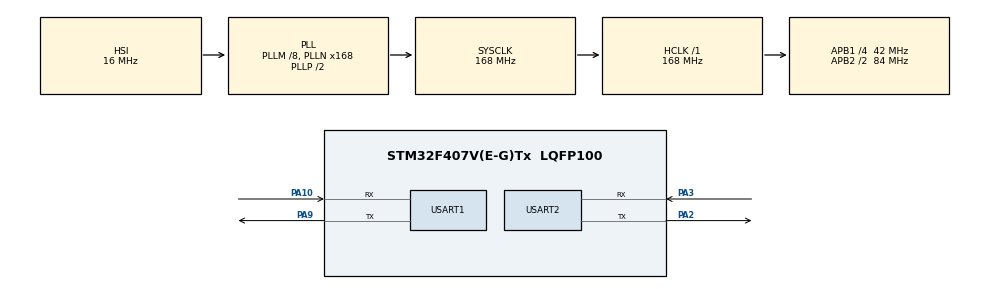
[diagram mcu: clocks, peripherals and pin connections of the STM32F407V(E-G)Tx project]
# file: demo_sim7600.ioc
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Mcu.Family=STM32F4
Mcu.Name=STM32F407V(E-G)Tx
Mcu.Package=LQFP100
NVIC.PriorityGroup=NVIC_PRIORITYGROUP_4
NVIC.USART1_IRQn=true\:0\:0\:false\:false\:true\:true\:true
NVIC.USART2_IRQn=true\:0\:0\:false\:false\:true\:true\:true
PA10.Mode=Asynchronous
PA10.Signal=USART1_RX
PA13.Mode=Serial_Wire
PA13.Signal=SYS_JTMS-SWDIO
PA14.Mode=Serial_Wire
PA14.Signal=SYS_JTCK-SWCLK
PA2.Mode=Asynchronous
PA2.Signal=USART2_TX
PA3.Mode=Asynchronous
PA3.Signal=USART2_RX
PA9.Mode=Asynchronous
PA9.Signal=USART1_TX
PH0-OSC_IN.Mode=HSE-External-Oscillator
PH0-OSC_IN.Signal=RCC_OSC_IN
PH1-OSC_OUT.Mode=HSE-External-Oscillator
PH1-OSC_OUT.Signal=RCC_OSC_OUT
ProjectManager.HeapSize=0x200
ProjectManager.StackSize=0x400
ProjectManager.TargetToolchain=STM32CubeIDE
RCC.48MHZClocksFreq_Value=84000000
RCC.AHBFreq_Value=168000000
RCC.APB1CLKDivider=RCC_HCLK_DIV4
RCC.APB1Freq_Value=42000000
RCC.APB1TimFreq_Value=84000000
RCC.APB2CLKDivider=RCC_HCLK_DIV2
RCC.APB2Freq_Value=84000000
RCC.APB2TimFreq_Value=168000000
RCC.CortexFreq_Value=168000000
RCC.HCLKFreq_Value=168000000
RCC.HSE_VALUE=25000000
RCC.HSI_VALUE=16000000
RCC.LSE_VALUE=32768
RCC.PLLM=8
RCC.PLLN=168
RCC.SYSCLKFreq_VALUE=168000000
RCC.SYSCLKSource=RCC_SYSCLKSOURCE_PLLCLK
RCC.VCOOutputFreq_Value=336000000
USART1.VirtualMode=VM_ASYNC
USART2.VirtualMode=VM_ASYNC
board=custom

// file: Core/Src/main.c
/* USER CODE BEGIN Header */
/**
  ******************************************************************************
  * @file           : main.c
  * @brief          : Main program body
  ******************************************************************************
  * @attention
  *
  * <h2><center>&copy; Copyright (c) 2021 STMicroelectronics.
  * All rights reserved.</center></h2>
  *
  * This software component is licensed by ST under BSD 3-Clause license,
  * the "License"; You may not use this file except in compliance with the
  * License. You may obtain a copy of the License at:
  *                        opensource.org/licenses/BSD-3-Clause
  *
  ******************************************************************************
  */
/* USER CODE END Header */
#include "main.h"
#include "sim7600.h"
#include "string.h"
#include "stdlib.h"

UART_HandleTypeDef huart1;
UART_HandleTypeDef huart2;

void SystemClock_Config(void);
static void MX_GPIO_Init(void);
static void MX_USART1_UART_Init(void);
static void MX_USART2_UART_Init(void);
/* USER CODE BEGIN PFP */
char payload[500];
/* USER CODE END PFP */

int main(void)
{

  /* MCU Configuration--------------------------------------------------------*/

  /* Reset of all peripherals, Initializes the Flash interface and the Systick. */
  HAL_Init();

  /* Configure the system clock */
  SystemClock_Config();

  /* Initialize all configured peripherals */
  MX_GPIO_Init();
  MX_USART1_UART_Init();
  MX_USART2_UART_Init();
  /* USER CODE BEGIN 2 */
  __HAL_UART_ENABLE_IT(&huart2, UART_IT_RXNE);
  INIT_SIM7600();
  SETUP_CONNECTION( "3.226.137.205","yktdxpqb","VKCG6yboYrYd",19613);
  /* USER CODE END 2 */
  /* Infinite loop */
  /* USER CODE BEGIN WHILE */
  while (1)
  {
	  PUBLISH_TELEMETRY("upstream/telemetry/608a78baaa969877dec4e6f4");
	  HAL_Delay(3000);
    /* USER CODE END WHILE */

  }
}

void SystemClock_Config(void)
{
  RCC_OscInitTypeDef RCC_OscInitStruct = {0};
  RCC_ClkInitTypeDef RCC_ClkInitStruct = {0};

  /** Configure the main internal regulator output voltage
  */
  __HAL_RCC_PWR_CLK_ENABLE();
  __HAL_PWR_VOLTAGESCALING_CONFIG(PWR_REGULATOR_VOLTAGE_SCALE1);
  /** Initializes the RCC Oscillators according to the specified parameters
  * in the RCC_OscInitTypeDef structure.
  */
  RCC_OscInitStruct.OscillatorType = RCC_OSCILLATORTYPE_HSI;
  RCC_OscInitStruct.HSIState = RCC_HSI_ON;
  RCC_OscInitStruct.HSICalibrationValue = RCC_HSICALIBRATION_DEFAULT;
  RCC_OscInitStruct.PLL.PLLState = RCC_PLL_ON;
  RCC_OscInitStruct.PLL.PLLSource = RCC_PLLSOURCE_HSI;
  RCC_OscInitStruct.PLL.PLLM = 8;
  RCC_OscInitStruct.PLL.PLLN = 168;
  RCC_OscInitStruct.PLL.PLLP = RCC_PLLP_DIV2;
  RCC_OscInitStruct.PLL.PLLQ = 4;
  if (HAL_RCC_OscConfig(&RCC_OscInitStruct) != HAL_OK)
  {
    Error_Handler();
  }
  /** Initializes the CPU, AHB and APB buses clocks
  */
  RCC_ClkInitStruct.ClockType = RCC_CLOCKTYPE_HCLK|RCC_CLOCKTYPE_SYSCLK
                              |RCC_CLOCKTYPE_PCLK1|RCC_CLOCKTYPE_PCLK2;
  RCC_ClkInitStruct.SYSCLKSource = RCC_SYSCLKSOURCE_PLLCLK;
  RCC_ClkInitStruct.AHBCLKDivider = RCC_SYSCLK_DIV1;
  RCC_ClkInitStruct.APB1CLKDivider = RCC_HCLK_DIV4;
  RCC_ClkInitStruct.APB2CLKDivider = RCC_HCLK_DIV2;

  if (HAL_RCC_ClockConfig(&RCC_ClkInitStruct, FLASH_LATENCY_5) != HAL_OK)
  {
    Error_Handler();
  }
}

static void MX_USART1_UART_Init(void)
{

  huart1.Instance = USART1;
  huart1.Init.BaudRate = 9600;
  huart1.Init.WordLength = UART_WORDLENGTH_8B;
  huart1.Init.StopBits = UART_STOPBITS_1;
  huart1.Init.Parity = UART_PARITY_NONE;
  huart1.Init.Mode = UART_MODE_TX_RX;
  huart1.Init.HwFlowCtl = UART_HWCONTROL_NONE;
  huart1.Init.OverSampling = UART_OVERSAMPLING_16;
  if (HAL_UART_Init(&huart1) != HAL_OK)
  {
    Error_Handler();
  }

}

static void MX_USART2_UART_Init(void)
{

  huart2.Instance = USART2;
  huart2.Init.BaudRate = 115200;
  huart2.Init.WordLength = UART_WORDLENGTH_8B;
  huart2.Init.StopBits = UART_STOPBITS_1;
  huart2.Init.Parity = UART_PARITY_NONE;
  huart2.Init.Mode = UART_MODE_TX_RX;
  huart2.Init.HwFlowCtl = UART_HWCONTROL_NONE;
  huart2.Init.OverSampling = UART_OVERSAMPLING_16;
  if (HAL_UART_Init(&huart2) != HAL_OK)
  {
    Error_Handler();
  }

}

static void MX_GPIO_Init(void)
{
  GPIO_InitTypeDef GPIO_InitStruct = {0};

  /* GPIO Ports Clock Enable */
  __HAL_RCC_GPIOH_CLK_ENABLE();
  __HAL_RCC_GPIOA_CLK_ENABLE();
  __HAL_RCC_GPIOD_CLK_ENABLE();

  /*Configure GPIO pin Output Level */
  HAL_GPIO_WritePin(GPIOD, GPIO_PIN_12|GPIO_PIN_13, GPIO_PIN_RESET);

  /*Configure GPIO pins : PD12 PD13 */
  GPIO_InitStruct.Pin = GPIO_PIN_12|GPIO_PIN_13;
  GPIO_InitStruct.Mode = GPIO_MODE_OUTPUT_PP;
  GPIO_InitStruct.Pull = GPIO_NOPULL;
  GPIO_InitStruct.Speed = GPIO_SPEED_FREQ_LOW;
  HAL_GPIO_Init(GPIOD, &GPIO_InitStruct);

}

void Error_Handler(void)
{
}

/************************ (C) COPYRIGHT STMicroelectronics *****END OF FILE****/
